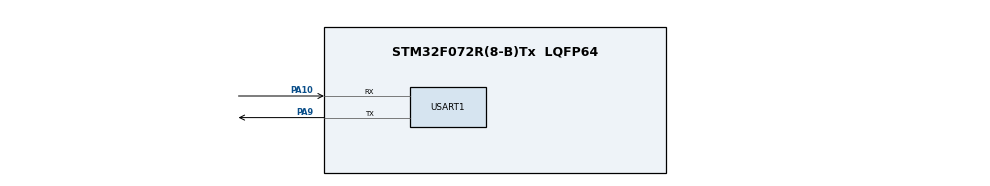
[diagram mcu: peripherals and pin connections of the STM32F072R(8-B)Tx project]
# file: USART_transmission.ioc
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Mcu.Family=STM32F0
Mcu.Name=STM32F072R(8-B)Tx
Mcu.Package=LQFP64
NVIC.USART1_IRQn=true\:0\:0\:false\:false\:true\:true\:true\:true
PA10.Mode=Asynchronous
PA10.Signal=USART1_RX
PA9.Mode=Asynchronous
PA9.Signal=USART1_TX
PF0-OSC_IN.Mode=HSE-External-Oscillator
PF0-OSC_IN.Signal=RCC_OSC_IN
PF1-OSC_OUT.Mode=HSE-External-Oscillator
PF1-OSC_OUT.Signal=RCC_OSC_OUT
ProjectManager.HeapSize=0x200
ProjectManager.StackSize=0x400
ProjectManager.TargetToolchain=STM32CubeIDE
RCC.AHBFreq_Value=48000000
RCC.APB1Freq_Value=48000000
RCC.APB1TimFreq_Value=48000000
RCC.HCLKFreq_Value=48000000
RCC.PLLMUL=RCC_PLL_MUL6
RCC.SYSCLKFreq_VALUE=48000000
RCC.SYSCLKSource=RCC_SYSCLKSOURCE_PLLCLK
USART1.VirtualMode-Asynchronous=VM_ASYNC
board=STM32F072B-DISCO

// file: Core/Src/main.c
#include "main.h"
#include "stm32f0xx_hal_uart.h"
#include <string.h>

void SystemClock_Config(void);
static void MX_GPIO_Init(void);
static void MX_USART1_UART_Init(void);
void HAL_UART_TxCpltCallback(UART_HandleTypeDef *huart);

UART_HandleTypeDef huart1;

/* Buffer to store the data to be transmitted */
uint8_t test[] = "Hello World! \r\n";

/* UART Tx Transfer completed callback */
void HAL_UART_TxCpltCallback(UART_HandleTypeDef *huart)
{
  /* Send the data again */
  HAL_UART_Transmit_IT(huart, test, strlen((char*)test));
}

int main(void)
{
  /* MCU Configuration--------------------------------------------------------*/

  /* Reset of all peripherals, Initializes the Flash interface and the Systick. */
  HAL_Init();

  /* Configure the system clock */
  SystemClock_Config();

  /* Initialize all configured peripherals */
  MX_GPIO_Init();
  MX_USART1_UART_Init();

  /* Start the transmission */
  HAL_UART_Transmit_IT(&huart1, test, strlen((char*)test));

  /* Infinite loop */
  while (1)
  {

  }
}

static void MX_USART1_UART_Init(void)
{
  huart1.Instance = USART1;
  huart1.Init.BaudRate = 38400;
  huart1.Init.WordLength = UART_WORDLENGTH_8B;
  huart1.Init.StopBits = UART_STOPBITS_1;
  huart1.Init.Parity = UART_PARITY_NONE;
  huart1.Init.Mode = UART_MODE_TX_RX;
  huart1.Init.HwFlowCtl = UART_HWCONTROL_NONE;
  huart1.Init.OverSampling = UART_OVERSAMPLING_16;
  huart1.Init.OneBitSampling = UART_ONE_BIT_SAMPLE_DISABLE;
  huart1.AdvancedInit.AdvFeatureInit = UART_ADVFEATURE_NO_INIT;
  if (HAL_UART_Init(&huart1) != HAL_OK)
  {
    Error_Handler();
  }
}

static void MX_GPIO_Init(void)
{
  GPIO_InitTypeDef GPIO_InitStruct = {0};

  /* GPIO Ports Clock Enable */
  __HAL_RCC_GPIOF_CLK_ENABLE();
  __HAL_RCC_GPIOC_CLK_ENABLE();
  __HAL_RCC_GPIOA_CLK_ENABLE();

  /*Configure GPIO pin Output Level */
  HAL_GPIO_WritePin(GPIOC, GPIO_PIN_7, GPIO_PIN_RESET);

  /*Configure GPIO pin : PC7 */
  GPIO_InitStruct.Pin = GPIO_PIN_7;
  GPIO_InitStruct.Mode = GPIO_MODE_OUTPUT_PP;
  GPIO_InitStruct.Pull = GPIO_NOPULL;
  GPIO_InitStruct.Speed = GPIO_SPEED_FREQ_LOW;
  HAL_GPIO_Init(GPIOC, &GPIO_InitStruct);

}

void Error_Handler(void)
{
  __disable_irq();
  while (1)
  {
  }
}

void SystemClock_Config(void)
{
  RCC_OscInitTypeDef RCC_OscInitStruct = {0};
  RCC_ClkInitTypeDef RCC_ClkInitStruct = {0};

  /**Configure the main internal regulator output voltage
  */
  __HAL_RCC_PWR_CLK_ENABLE();
  //__HAL_PWR_VOLTAGESCALING_CONFIG(PWR_REGULATOR_VOLTAGE_SCALE1);
  /**Initializes the RCC Oscillators according to the specified parameters
  * in the RCC_OscInitTypeDef structure.
  */
  RCC_OscInitStruct.OscillatorType = RCC_OSCILLATORTYPE_HSI;
  RCC_OscInitStruct.HSIState = RCC_HSI_ON;
  RCC_OscInitStruct.HSICalibrationValue = RCC_HSICALIBRATION_DEFAULT;
  RCC_OscInitStruct.PLL.PLLState = RCC_PLL_NONE;
  if (HAL_RCC_OscConfig(&RCC_OscInitStruct) != HAL_OK)
  {
    Error_Handler();
  }
  /**Initializes the CPU, AHB and APB buses clocks
  */
  RCC_ClkInitStruct.ClockType = RCC_CLOCKTYPE_HCLK|RCC_CLOCKTYPE_SYSCLK
                              |RCC_CLOCKTYPE_PCLK1;
  RCC_ClkInitStruct.SYSCLKSource = RCC_SYSCLKSOURCE_HSI;
  RCC_ClkInitStruct.AHBCLKDivider = RCC_SYSCLK_DIV1;
  RCC_ClkInitStruct.APB1CLKDivider = RCC_HCLK_DIV1;

  if (HAL_RCC_ClockConfig(&RCC_ClkInitStruct, FLASH_LATENCY_0) != HAL_OK)
  {
    Error_Handler();
  }
}
